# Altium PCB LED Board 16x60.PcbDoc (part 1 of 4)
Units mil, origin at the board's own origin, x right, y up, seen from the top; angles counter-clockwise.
Board outline 17002.17 x 16958.87 mil, 2 copper layers (Top Layer, Bottom Layer); 984 components, 0 nets, 1968 pads, 0 vias.

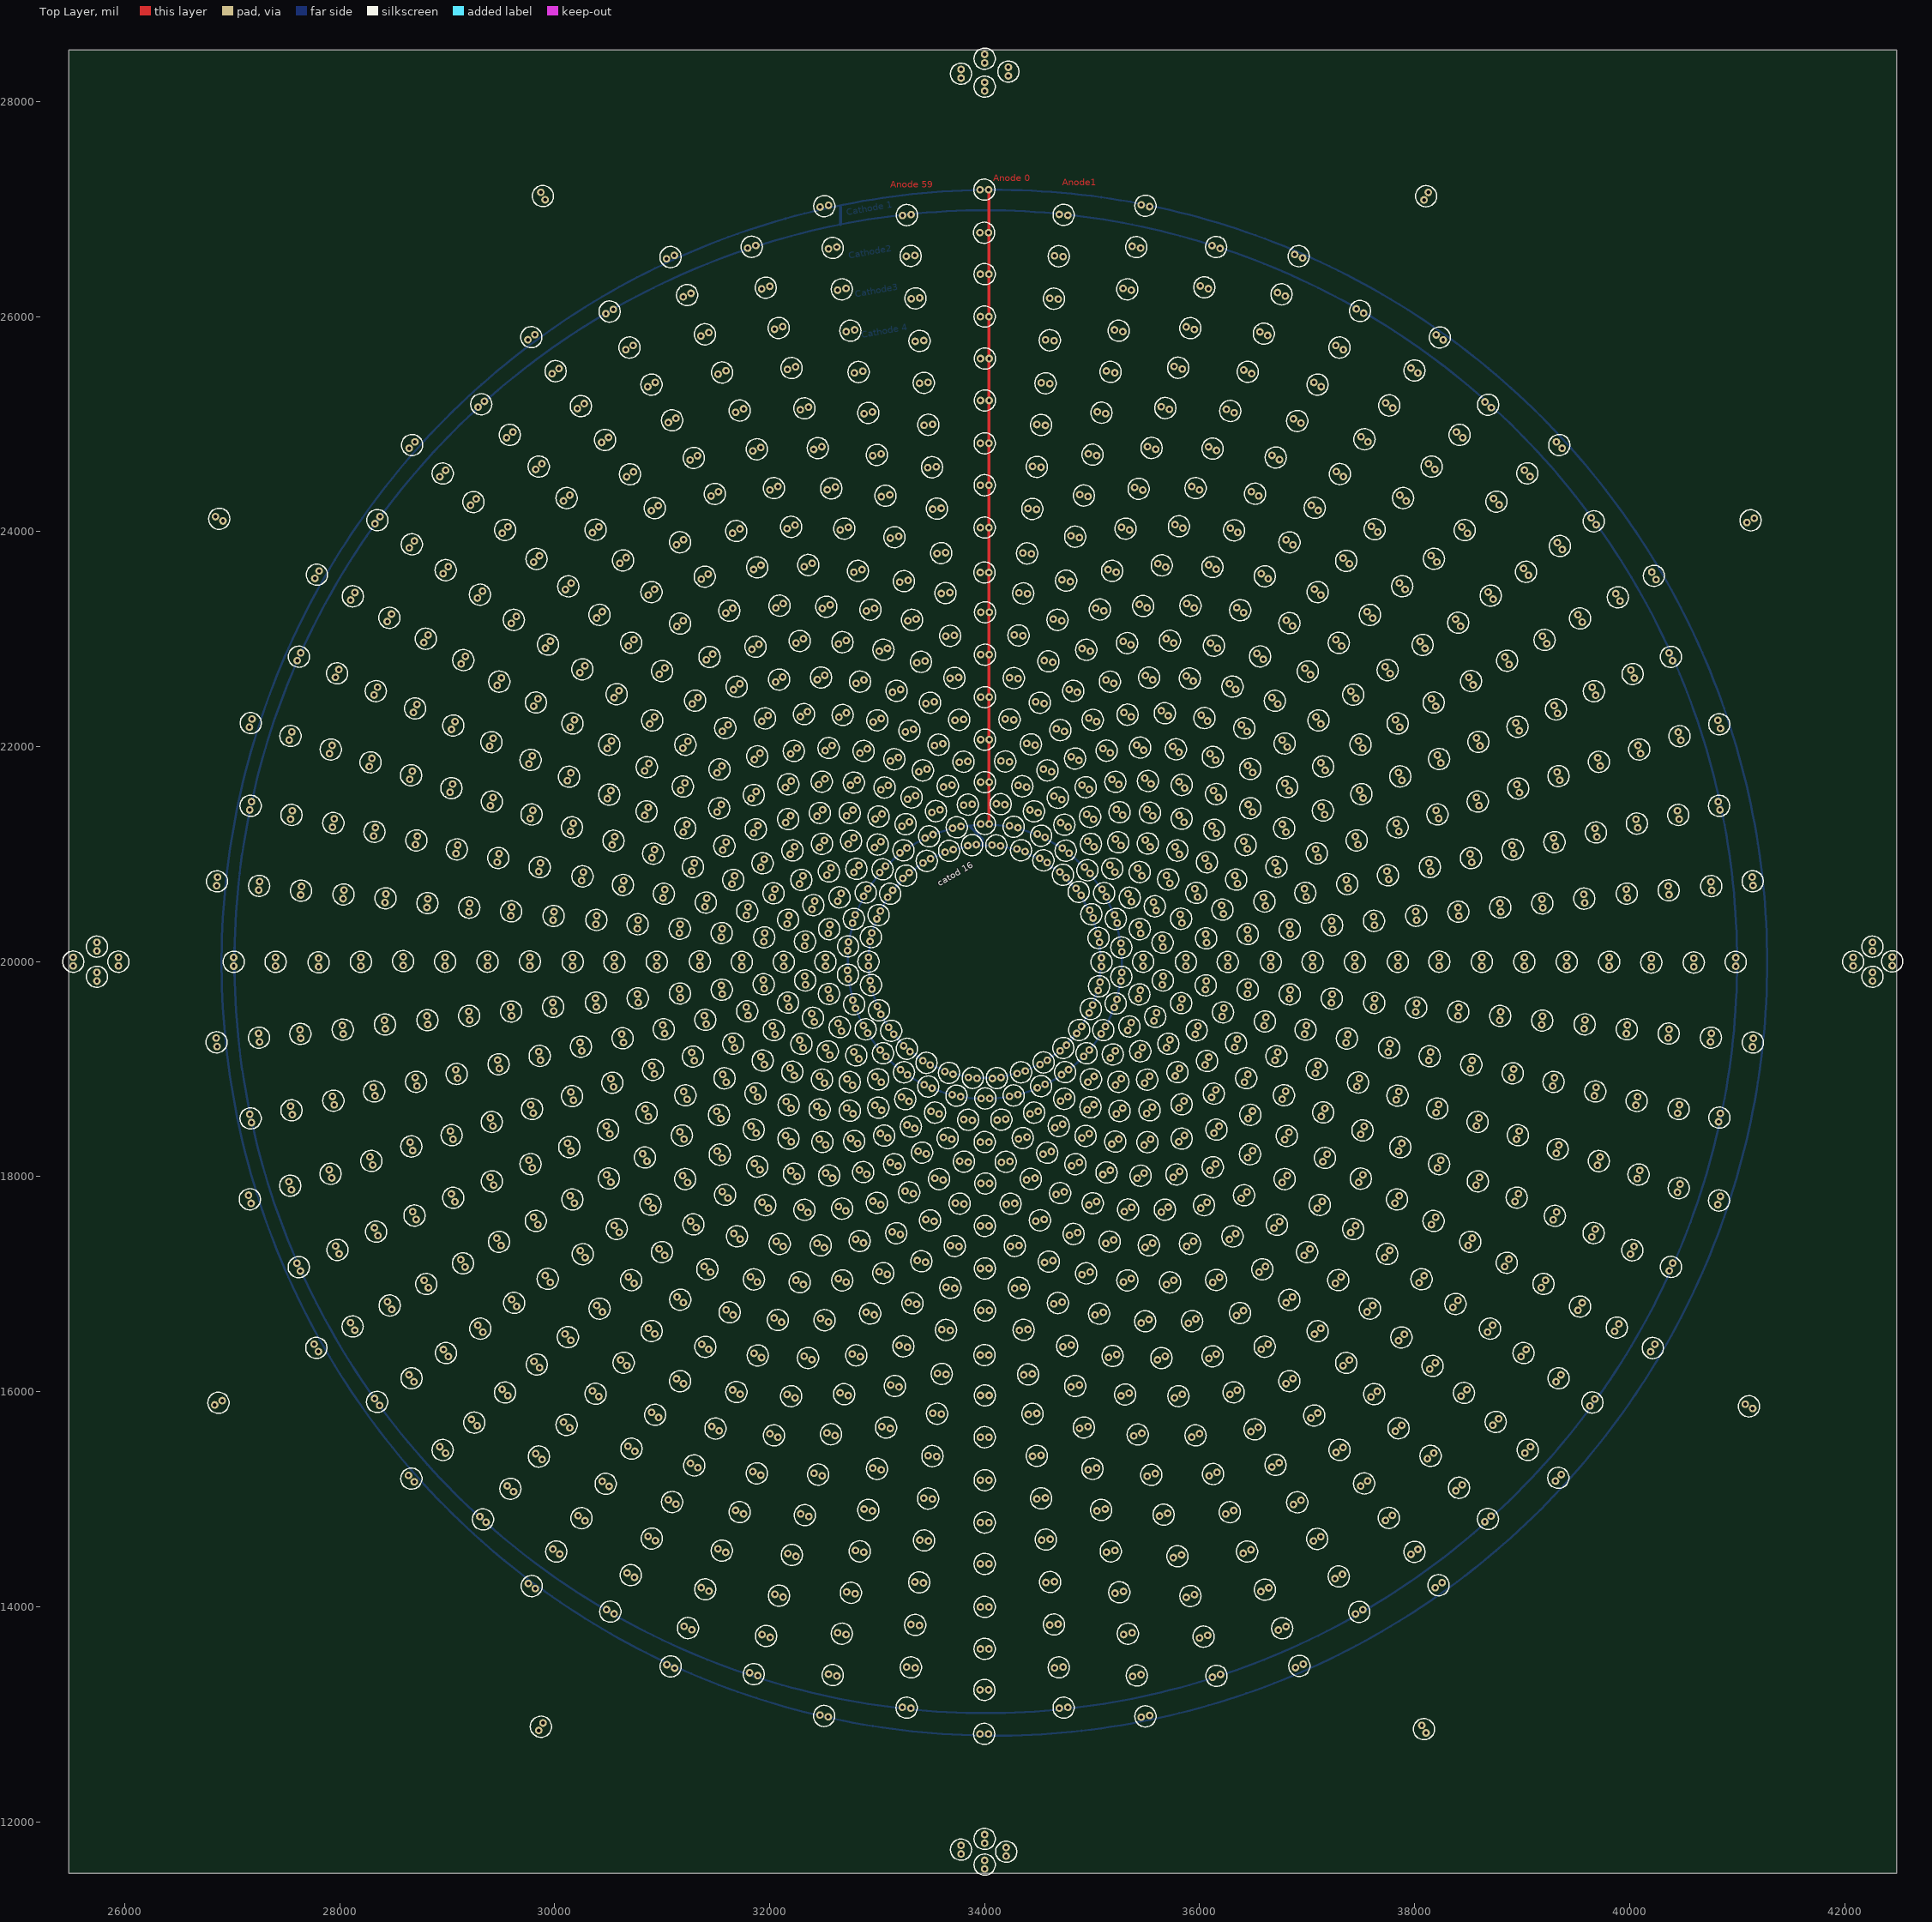
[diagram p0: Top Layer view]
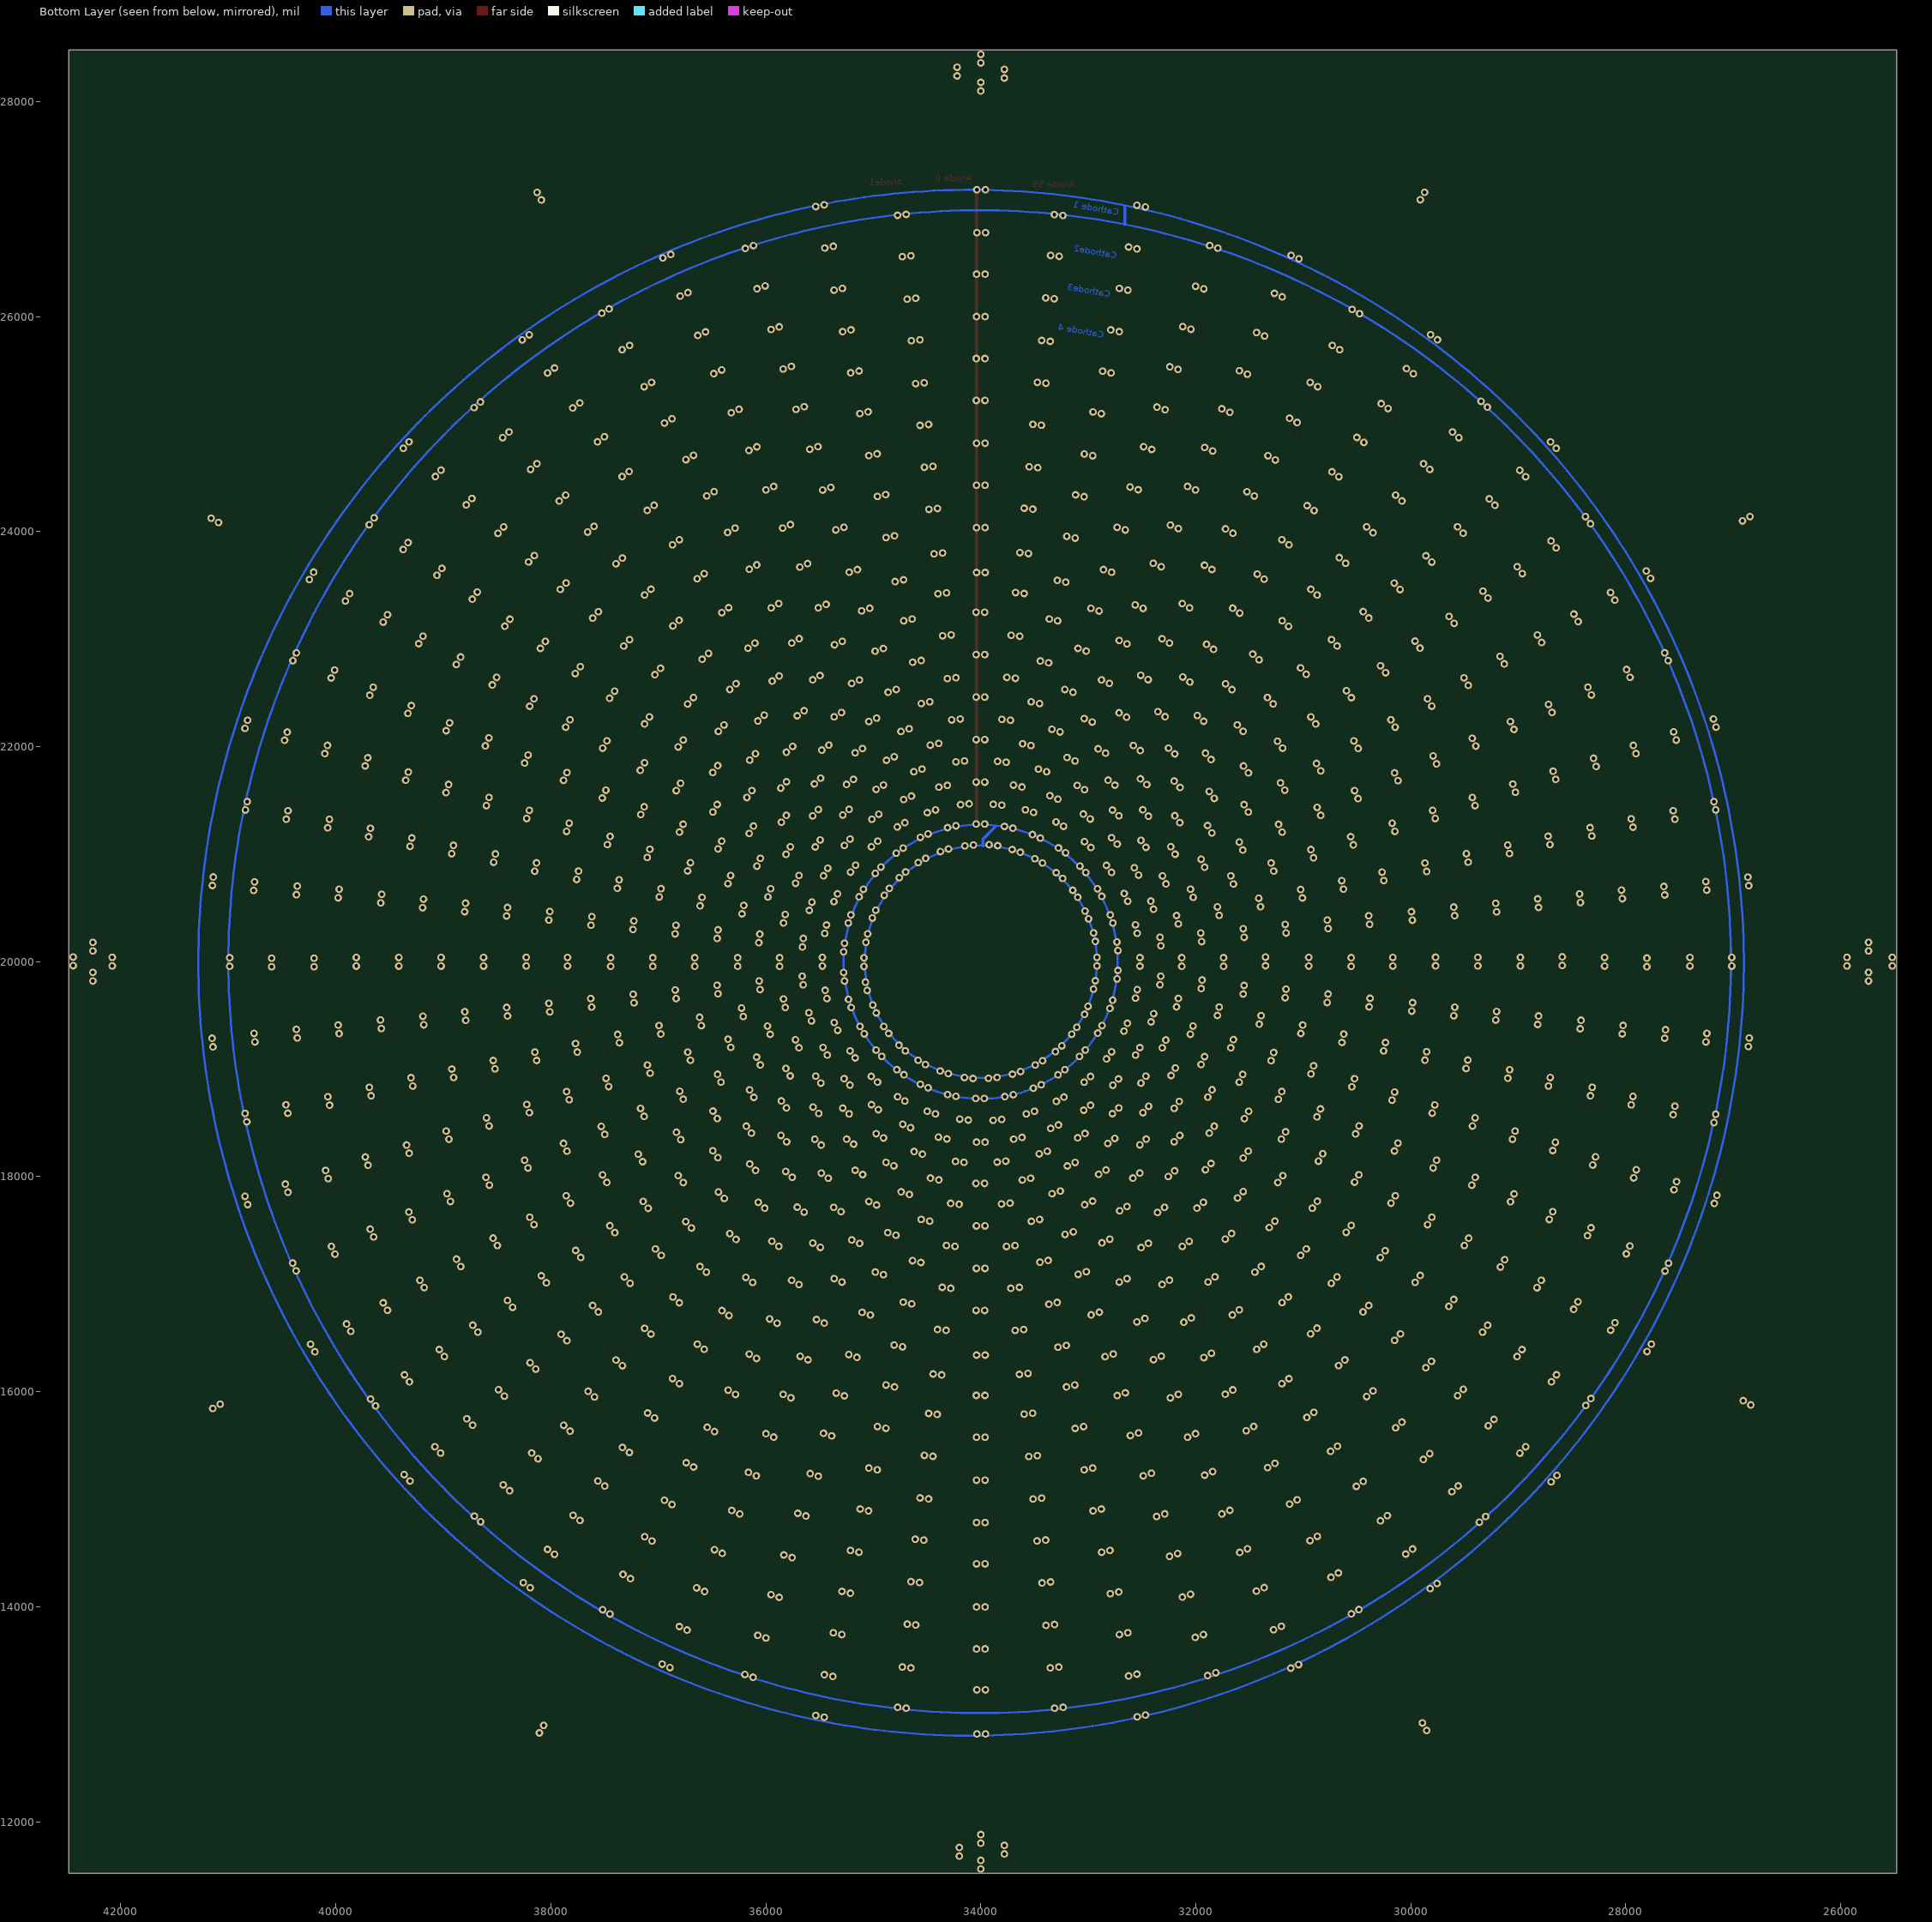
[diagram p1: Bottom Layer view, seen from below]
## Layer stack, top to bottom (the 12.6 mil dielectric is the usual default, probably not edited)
Top Layer: signal copper 1.4
Dielectric: dielectric 12.6, FR-4, Dk 4.8
Bottom Layer: signal copper 1.4

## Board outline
25480.57,11520.57 42482.74,11520.57 42482.74,28479.43 25480.57,28479.43

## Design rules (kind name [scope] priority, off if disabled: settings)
Clearance [All] p1: gap=10
PolygonConnect [All] p1: connectstyle=Relief reliefconductorwidth=10 reliefentries=4 polygonreliefangle="90 Angle"
RoutingVias [All] p1: holewidth=28 width=50 viastyle="Through Hole" minholewidth=28 minwidth=50 maxholewidth=28 maxwidth=50
SilkscreenOverComponentPads [All] p1: minsilkscreentomaskgap=10
SolderMaskExpansion [All] p1: expansion=4
Width [All] p1: maxlimit=10 minlimit=10 preferedwidth=10
27 further rules are at their usual default settings.

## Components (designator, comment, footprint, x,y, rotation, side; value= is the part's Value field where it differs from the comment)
? "" "LED 5MM"#1 33273.72,13060.04 r354 top
? "" "LED 5MM"#2 32585.57,13363.9 r348 top
? "" "LED 5MM"#3 31850.9,13372.36 r342 top
? "" "LED 5MM"#4 31239.7,13801.26 r336 top
? "" "LED 5MM"#5 30517.32,13953.56 r330 top
? "" "LED 5MM"#6 30013.82,14512.85 r324 top
? "" "LED 5MM"#7 29332.22,14811.71 r318 top
? "" "LED 5MM"#8 28956.81,15457.17 r312 top
? "" "LED 5MM"#9 28347.15,15904.51 r306 top
? "" "LED 5MM"#10 28119.06,16606.48 r300 top
? "" "LED 5MM"#11 27617.85,17158.44 r294 top
? "" "LED 5MM"#12 27538.23,17916.2 r288 top
? "" "LED 5MM"#13 27170.12,18542.03 r282 top
? "" "LED 5MM"#14 27248.21,19292.85 r276 top
? "" "LED 5MM"#15 27012.42,19998.68 r270 top
? "" "LED 5MM"#16 27249.37,20705.29 r264 top
? "" "LED 5MM"#17 27170.12,21449.96 r78 top
? "" "LED 5MM"#18 27541.32,22099.25 r72 top
? "" "LED 5MM"#19 27619.78,22837.01 r66 top
? "" "LED 5MM"#20 28120.98,23398.98 r60 top
? "" "LED 5MM"#21 28350.22,24107.11 r54 top
? "" "LED 5MM"#22 28957.58,24540.98 r48 top
? "" "LED 5MM"#23 29316.08,25185.67 r42 top
? "" "LED 5MM"#24 30007.68,25493.38 r36 top
? "" "LED 5MM"#25 30510.02,26048.03 r30 top
? "" "LED 5MM"#26 31231.61,26201.12 r24 top
? "" "LED 5MM"#27 31832.81,26650.02 r18 top
? "" "LED 5MM"#28 32585.89,26639.68 r12 top
? "" "LED 5MM"#29 33275.63,26945.43 r6 top
? "" "LED 5MM"#30 33994.92,26781.18 r0 top
? "" "LED 5MM"#31 34734.21,26947.34 r354 top
? "" "LED 5MM"#32 35410.79,26646.93 r348 top
? "" "LED 5MM"#33 36153.19,26648.09 r342 top
? "" "LED 5MM"#34 36761.1,26207.97 r336 top
? "" "LED 5MM"#35 37491.75,26053.03 r330 top
? "" "LED 5MM"#36 37998.33,25499.53 r324 top
? "" "LED 5MM"#37 38683.78,25180.67 r318 top
? "" "LED 5MM"#38 39047.85,24543.01 r312 top
? "" "LED 5MM"#39 39666.16,24096.73 r306 top
? "" "LED 5MM"#40 39891.38,23389.45 r300 top
? "" "LED 5MM"#41 40384.06,22835.83 r294 top
? "" "LED 5MM"#42 40464.37,22098.11 r288 top
? "" "LED 5MM"#43 40832.79,21449.96 r282 top
? "" "LED 5MM"#44 40760.18,20702.99 r276 top
? "" "LED 5MM"#45 40987.44,19997.54 r270 top
? "" "LED 5MM"#46 40756.71,19292.85 r264 top
? "" "LED 5MM"#47 40835.89,18549.33 r258 top
? "" "LED 5MM"#48 40457.83,17893.48 r252 top
? "" "LED 5MM"#49 40385.08,17160.37 r246 top
? "" "LED 5MM"#50 39880.87,16596.06 r240 top
? "" "LED 5MM"#51 39653.86,15899.51 r234 top
? "" "LED 5MM"#52 39052.32,15458.27 r228 top
? "" "LED 5MM"#53 38682.62,14815.94 r222 top
? "" "LED 5MM"#54 37998.39,14509.72 r216 top
? "" "LED 5MM"#55 37484.06,13951.26 r210 top
? "" "LED 5MM"#56 36767.87,13798.88 r204 top
? "" "LED 5MM"#57 36157.03,13356.22 r198 top
? "" "LED 5MM"#58 35415.45,13359.61 r192 top
? "" "LED 5MM"#59 34734.21,13060.04 r186 top
? "" "LED 5MM"#60 33996.85,13225.79 r0 top
? "" "LED 5MM"#61 33353.72,13830.04 r354 top
? "" "LED 5MM"#62 32755.57,14128.9 r348 top
? "" "LED 5MM"#63 32085.9,14102.36 r342 top
? "" "LED 5MM"#64 31554.7,14521.26 r336 top
? "" "LED 5MM"#65 30902.32,14633.56 r330 top
? "" "LED 5MM"#66 30473.82,15142.85 r324 top
? "" "LED 5MM"#67 29852.22,15396.71 r318 top
? "" "LED 5MM"#68 29536.81,15992.17 r312 top
? "" "LED 5MM"#69 28987.15,16359.51 r306 top
? "" "LED 5MM"#70 28804.06,17001.48 r300 top
? "" "LED 5MM"#71 28337.85,17488.44 r294 top
? "" "LED 5MM"#72 28293.23,18146.2 r288 top
? "" "LED 5MM"#73 27940.12,18707.03 r282 top
? "" "LED 5MM"#74 28028.21,19367.85 r276 top
? "" "LED 5MM"#75 27802.42,19993.68 r270 top
? "" "LED 5MM"#76 28034.37,20625.29 r264 top
? "" "LED 5MM"#77 27940.12,21289.96 r78 top
? "" "LED 5MM"#78 28286.32,21854.25 r72 top
? "" "LED 5MM"#79 28334.78,22517.01 r66 top
? "" "LED 5MM"#80 28800.98,23003.98 r60 top
? "" "LED 5MM"#81 28985.22,23642.11 r54 top
? "" "LED 5MM"#82 29537.58,24015.98 r48 top
? "" "LED 5MM"#83 29851.08,24605.67 r42 top
? "" "LED 5MM"#84 30467.68,24853.38 r36 top
? "" "LED 5MM"#85 30900.02,25368.03 r30 top
? "" "LED 5MM"#86 31556.61,25481.12 r24 top
? "" "LED 5MM"#87 32082.81,25895.02 r18 top
? "" "LED 5MM"#88 32750.57,25869.63 r12 top
? "" "LED 5MM"#89 33355.63,26170.43 r6 top
? "" "LED 5MM"#90 33999.92,26001.18 r0 top
? "" "LED 5MM"#91 34644.21,26167.34 r354 top
? "" "LED 5MM"#92 35246.2,25869.63 r348 top
? "" "LED 5MM"#93 35913.19,25893.09 r342 top
? "" "LED 5MM"#94 36447.09,25487.28 r336 top
? "" "LED 5MM"#95 37096.75,25368.03 r330 top
? "" "LED 5MM"#96 37533.33,24859.53 r324 top
? "" "LED 5MM"#97 38158.78,24605.67 r318 top
? "" "LED 5MM"#98 38465.35,24014.07 r312 top
? "" "LED 5MM"#99 39036.16,23626.73 r306 top
? "" "LED 5MM"#100 39208.88,22992.81 r300 top
? "" "LED 5MM"#101 39668.15,22515.85 r294 top
? "" "LED 5MM"#102 39714.7,21859.25 r288 top
? "" "LED 5MM"#103 40067.79,21284.96 r282 top
? "" "LED 5MM"#104 39973.56,20633.37 r276 top
? "" "LED 5MM"#105 40202.44,19992.54 r270 top
? "" "LED 5MM"#106 39973.56,19370.94 r264 top
? "" "LED 5MM"#107 40065.89,18704.33 r258 top
? "" "LED 5MM"#108 39713.54,18145.06 r252 top
? "" "LED 5MM"#109 39665.08,17475.37 r246 top
? "" "LED 5MM"#110 39198.88,17002.24 r240 top
? "" "LED 5MM"#111 39013.86,16359.51 r234 top
? "" "LED 5MM"#112 38459.19,15988.31 r228 top
? "" "LED 5MM"#113 38148.29,15402.52 r222 top
? "" "LED 5MM"#114 37530.25,15145.92 r216 top
? "" "LED 5MM"#115 37092.82,14630.53 r210 top
? "" "LED 5MM"#116 36441.32,14513.17 r204 top
? "" "LED 5MM"#117 35913.88,14098.96 r198 top
? "" "LED 5MM"#118 35252.34,14133.9 r192 top
? "" "LED 5MM"#119 34644.15,13833.94 r186 top
? "" "LED 5MM"#120 33999.88,13997.82 r0 top
? "" "LED 5MM"#121 35189.83,16332.24 r198 top
? "" "LED 5MM"#122 34403.84,16160.39 r186 top
? "" "LED 5MM"#123 33600.44,16165.06 r354 top
? "" "LED 5MM"#124 32805.82,16338.11 r342 top
? "" "LED 5MM"#125 32076.09,16666.48 r330 top
? "" "LED 5MM"#126 31419.34,17138.56 r318 top
? "" "LED 5MM"#127 30891.41,17739.66 r306 top
? "" "LED 5MM"#128 30495.84,18434.67 r294 top
? "" "LED 5MM"#129 30243.28,19208.98 r282 top
? "" "LED 5MM"#130 30166.78,19998.97 r270 top
? "" "LED 5MM"#131 30258.28,20793.86 r78 top
? "" "LED 5MM"#132 30506.35,21553.78 r66 top
? "" "LED 5MM"#133 30906.15,22244.15 r54 top
? "" "LED 5MM"#134 31439.46,22834.9 r42 top
? "" "LED 5MM"#135 32091.35,23311.85 r30 top
? "" "LED 5MM"#136 32820.44,23635.08 r18 top
? "" "LED 5MM"#137 33595.55,23800.61 r6 top
? "" "LED 5MM"#138 34395.07,23798.03 r354 top
? "" "LED 5MM"#139 35185.19,23635.45 r342 top
? "" "LED 5MM"#140 35914.68,23311.61 r330 top
? "" "LED 5MM"#141 36561.92,22840.14 r318 top
? "" "LED 5MM"#142 37104.97,22244.38 r306 top
? "" "LED 5MM"#143 37504.18,21558.52 r294 top
? "" "LED 5MM"#144 37751.25,20803.6 r282 top
? "" "LED 5MM"#145 36122.57,21904.92 r312 top
? "" "LED 5MM"#146 36471.56,21427.52 r300 top
? "" "LED 5MM"#147 36714.3,20882.12 r288 top
? "" "LED 5MM"#148 36838.95,20298.25 r276 top
? "" "LED 5MM"#149 36838.22,19696.32 r264 top
? "" "LED 5MM"#150 36713.95,19120.71 r252 top
? "" "LED 5MM"#151 36471.07,18575.55 r240 top
? "" "LED 5MM"#152 36122.22,18088.52 r228 top
? "" "LED 5MM"#153 35675.88,17692.95 r216 top
? "" "LED 5MM"#154 35163.08,17395.61 r204 top
? "" "LED 5MM"#155 34595.87,17210.01 r192 top
? "" "LED 5MM"#156 34269.72,18755.55 r192 top
? "" "LED 5MM"#157 34006.71,18727.78 r180 top
? "" "LED 5MM"#158 33737.22,18753.7 r348 top
? "" "LED 5MM"#159 33474.19,18838.9 r336 top
? "" "LED 5MM"#160 33249.15,18971.34 r324 top
? "" "LED 5MM"#161 33054.67,19148.23 r312 top
? "" "LED 5MM"#162 32891.67,19370.49 r300 top
? "" "LED 5MM"#163 32785.18,19603.88 r288 top
? "" "LED 5MM"#164 32727.76,19878.92 r276 top
? "" "LED 5MM"#165 32728.68,20142.87 r264 top
? "" "LED 5MM"#166 32783.33,20397.54 r72 top
? "" "LED 5MM"#167 32893.52,20642.97 r60 top
? "" "LED 5MM"#168 33050.04,20858.74 r48 top
? "" "LED 5MM"#169 33243.6,21035.63 r36 top
? "" "LED 5MM"#170 33482.54,21166.22 r24 top
? "" "LED 5MM"#171 33740.37,21250.35 r12 top
? "" "LED 5MM"#172 34002.09,21281.04 r0 top
? "" "LED 5MM"#173 34269.72,21255.12 r348 top
? "" "LED 5MM"#174 34525.33,21171.77 r336 top
? "" "LED 5MM"#175 34754.07,21032.85 r324 top
? "" "LED 5MM"#176 34955.04,20850.41 r312 top
? "" "LED 5MM"#177 35111.56,20638.33 r300 top
? "" "LED 5MM"#178 35219.92,20397.54 r288 top
? "" "LED 5MM"#179 35271.77,20131.75 r276 top
? "" "LED 5MM"#180 35271.77,19859.47 r264 top
? "" "LED 5MM"#181 35218.07,19611.28 r252 top
? "" "LED 5MM"#182 35103.23,19363.09 r240 top
? "" "LED 5MM"#183 34947.64,19148.23 r228 top
? "" "LED 5MM"#184 34747.6,18972.26 r216 top
? "" "LED 5MM"#185 34525.33,18842.62 r204 top
? "" "LED 5MM"#186 34987.85,19560.04 r246 top
? "" "LED 5MM"#187 34879.22,19364.69 r234 top
? "" "LED 5MM"#188 34731.21,19197.36 r222 top
? "" "LED 5MM"#189 34548.51,19062.66 r210 top
? "" "LED 5MM"#190 34339.07,18971.06 r198 top
? "" "LED 5MM"#191 34112.45,18917.36 r186 top
? "" "LED 5MM"#192 33888.91,18919.03 r354 top
? "" "LED 5MM"#193 33667.87,18965.35 r342 top
? "" "LED 5MM"#194 33458.48,19059.03 r330 top
? "" "LED 5MM"#195 33275.43,19190 r318 top
? "" "LED 5MM"#196 33130.05,19356.94 r306 top
? "" "LED 5MM"#197 33017.41,19547.32 r294 top
? "" "LED 5MM"#198 32942.43,19783.54 r282 top
? "" "LED 5MM"#199 32918.91,20000.63 r270 top
? "" "LED 5MM"#200 32941.25,20228.25 r78 top
? "" "LED 5MM"#201 33012.74,20434.01 r66 top
? "" "LED 5MM"#202 33120.22,20631.89 r54 top
? "" "LED 5MM"#203 33268.59,20801.26 r42 top
? "" "LED 5MM"#204 33461.33,20937.4 r30 top
? "" "LED 5MM"#205 33669.13,21030.96 r18 top
? "" "LED 5MM"#206 33881.82,21083.76 r6 top
? "" "LED 5MM"#207 34107.9,21081.24 r354 top
? "" "LED 5MM"#208 34458.66,21398.66 r342 top
? "" "LED 5MM"#209 34546.63,20942.37 r330 top
? "" "LED 5MM"#210 34728.65,20808.11 r318 top
? "" "LED 5MM"#211 34874.14,20649.42 r306 top
? "" "LED 5MM"#212 34992.59,20442 r294 top
? "" "LED 5MM"#213 35060,20220 r282 top
? "" "LED 5MM"#214 35086.84,19995.51 r270 top
? "" "LED 5MM"#215 35064.6,19771.24 r258 top
? "" "LED 5MM"#216 32328.6,20187.32 r264 top
? "" "LED 5MM"#217 26857.85,20747.01 r264 top
? "" "LED 5MM"#218 27639.37,20660.29 r264 top
? "" "LED 5MM"#219 28814.8,20544.86 r264 top
? "" "LED 5MM"#220 30771.46,20347.78 r264 top
? "" "LED 5MM"#221 29988.82,20425.29 r264 top
? "" "LED 5MM"#222 29204.34,20503.13 r264 top
? "" "LED 5MM"#223 31553.44,20266.04 r264 top
? "" "LED 5MM"#224 41146.71,19247.85 r264 top
? "" "LED 5MM"#225 35657.05,19825.22 r264 top
? "" "LED 5MM"#226 36447.93,19740.92 r264 top
? "" "LED 5MM"#227 37229.49,19656.53 r264 top
? "" "LED 5MM"#228 39186.48,19452.46 r264 top
? "" "LED 5MM"#229 38796.17,19494.94 r264 top
? "" "LED 5MM"#230 38014.39,19572.79 r264 top
? "" "LED 5MM"#231 40363.56,19330.94 r264 top
? "" "LED 5MM"#232 36927.87,13448.88 r204 top
? "" "LED 5MM"#233 36606.32,14158.17 r204 top
? "" "LED 5MM"#234 36124.68,15233.62 r204 top
? "" "LED 5MM"#235 35962.06,15593.58 r204 top
? "" "LED 5MM"#236 35644.07,16312.56 r204 top
? "" "LED 5MM"#237 35327.56,17035.02 r204 top
? "" "LED 5MM"#238 35005.06,17752.58 r204 top
? "" "LED 5MM"#239 36037.03,13721.22 r198 top
? "" "LED 5MM"#240 35793.88,14468.96 r198 top
? "" "LED 5MM"#241 35549.25,15225.94 r198 top
? "" "LED 5MM"#242 35306.91,15973.7 r198 top
? "" "LED 5MM"#243 35064.98,16725.59 r198 top
? "" "LED 5MM"#244 34943.09,17100.63 r198 top
? "" "LED 5MM"#245 34581.83,18222.11 r198 top
? "" "LED 5MM"#246 34195.63,18137.83 r186 top
? "" "LED 5MM"#247 34318.9,16966.36 r186 top
? "" "LED 5MM"#248 34362.4,16575.14 r186 top
? "" "LED 5MM"#249 34444.53,15793.68 r186 top
? "" "LED 5MM"#250 34524.55,15007.46 r186 top
? "" "LED 5MM"#251 34609.15,14228.94 r186 top
? "" "LED 5MM"#252 34689.21,13435.04 r186 top
? "" "LED 5MM"#253 34514.21,17594.21 r192 top
? "" "LED 5MM"#254 34681.75,16824.94 r192 top
? "" "LED 5MM"#255 34841.87,16053.05 r192 top
? "" "LED 5MM"#256 35002.07,15281.71 r192 top
? "" "LED 5MM"#257 35083.05,14899.76 r192 top
? "" "LED 5MM"#258 35332.34,13748.9 r192 top
? "" "LED 5MM"#259 35495.45,12979.61 r192 top
? "" "LED 5MM"#260 34938.39,18379.55 r210 top
? "" "LED 5MM"#261 35527.46,17361.81 r210 top
? "" "LED 5MM"#262 35724.98,17016.56 r210 top
? "" "LED 5MM"#263 36120.06,16329.11 r210 top
? "" "LED 5MM"#264 36510.87,15649.06 r210 top
? "" "LED 5MM"#265 36907.82,14970.53 r210 top
? "" "LED 5MM"#266 37294.06,14281.26 r210 top
? "" "LED 5MM"#267 35450.51,18009.11 r216 top
? "" "LED 5MM"#268 35910.9,17375.65 r216 top
? "" "LED 5MM"#269 36375.04,16731.28 r216 top
? "" "LED 5MM"#270 36835.13,16097.79 r216 top
? "" "LED 5MM"#271 37066.3,15778.29 r216 top
? "" "LED 5MM"#272 37760.26,14825.92 r216 top
? "" "LED 5MM"#273 38223.39,14199.72 r216 top
? "" "LED 5MM"#274 35254.17,18611.08 r222 top
? "" "LED 5MM"#275 36039.61,17735.02 r222 top
? "" "LED 5MM"#276 36305.49,17443.78 r222 top
? "" "LED 5MM"#277 36833.98,16853.78 r222 top
? "" "LED 5MM"#278 37363.25,16267.56 r222 top
? "" "LED 5MM"#279 37850,15660 r222 top
? "" "LED 5MM"#280 38412.62,15105.94 r222 top
? "" "LED 5MM"#281 35832.07,18353.62 r228 top
? "" "LED 5MM"#282 36413.37,17827.01 r228 top
? "" "LED 5MM"#283 36999.55,17297.6 r228 top
? "" "LED 5MM"#284 37584.54,16772.36 r228 top
? "" "LED 5MM"#285 37877.14,16504.51 r228 top
? "" "LED 5MM"#286 38754.19,15718.31 r228 top
? "" "LED 5MM"#287 39337.32,15198.27 r228 top
? "" "LED 5MM"#288 39338.86,16124.51 r234 top
? "" "LED 5MM"#289 38701.83,16586.06 r234 top
? "" "LED 5MM"#290 38064.84,17046.1 r234 top
? "" "LED 5MM"#291 37427.87,17512.28 r234 top
? "" "LED 5MM"#292 36790.9,17977.46 r234 top
? "" "LED 5MM"#293 36469.33,18209.19 r234 top
? "" "LED 5MM"#294 35511.63,18902.81 r234 top
? "" "LED 5MM"#295 40215.87,16406.06 r240 top
? "" "LED 5MM"#296 39538.88,16792.24 r240 top
? "" "LED 5MM"#297 38517.18,17393.82 r240 top
? "" "LED 5MM"#298 38176.33,17587.99 r240 top
? "" "LED 5MM"#299 37499.17,17981.71 r240 top
? "" "LED 5MM"#300 36810.79,18379.13 r240 top
? "" "LED 5MM"#301 36131.2,18772.22 r240 top
? "" "LED 5MM"#302 40025.08,17315.37 r246 top
? "" "LED 5MM"#303 39304.96,17635.37 r246 top
? "" "LED 5MM"#304 38587.97,17956.95 r246 top
? "" "LED 5MM"#305 37866.36,18273.9 r246 top
? "" "LED 5MM"#306 37148.58,18597.72 r246 top
? "" "LED 5MM"#307 36784.19,18757.46 r246 top
? "" "LED 5MM"#308 35707.97,19236.2 r246 top
? "" "LED 5MM"#309 40832.83,17778.48 r252 top
? "" "LED 5MM"#310 40083.54,18020.06 r252 top
? "" "LED 5MM"#311 38960.32,18386.22 r252 top
? "" "LED 5MM"#312 38585.93,18508.97 r252 top
? "" "LED 5MM"#313 37841.22,18753.84 r252 top
? "" "LED 5MM"#314 37088.98,19000.81 r252 top
? "" "LED 5MM"#315 36338.66,19240.83 r252 top
? "" "LED 5MM"#316 35827.44,19614.06 r258 top
? "" "LED 5MM"#317 36985.16,19366.83 r258 top
? "" "LED 5MM"#318 37370,19284.69 r258 top
? "" "LED 5MM"#319 38140.24,19120.12 r258 top
? "" "LED 5MM"#320 38912.62,18961.65 r258 top
? "" "LED 5MM"#321 39680.37,18792.4 r258 top
? "" "LED 5MM"#322 40455.89,18629.33 r258 top
? "" "LED 5MM"#323 38086.44,12860.67 r300 top
? "" "LED 5MM"#324 41111.16,15863.9 r330 top
? "" "LED 5MM"#325 34155.81,18530.51 r186 top
? "" "LED 5MM"#326 34354,18359.17 r192 top
? "" "LED 5MM"#327 34459.59,18596.26 r198 top
? "" "LED 5MM"#328 34689.25,18471.24 r204 top
? "" "LED 5MM"#329 34740.2,18724.07 r210 top
? "" "LED 5MM"#330 34984.68,18646.28 r216 top
? "" "LED 5MM"#331 34989.31,18906.51 r222 top
? "" "LED 5MM"#332 35244,18882.44 r228 top
? "" "LED 5MM"#333 35192.13,19137.11 r234 top
? "" "LED 5MM"#334 35447.74,19166.75 r240 top
? "" "LED 5MM"#335 35346.79,19397.34 r246 top
? "" "LED 5MM"#336 35586.65,19487.19 r252 top
? "" "LED 5MM"#337 35439.41,19695.55 r258 top
? "" "LED 5MM"#338 31076.48,26554.76 r24 top
? "" "LED 5MM"#339 31396.61,25836.12 r24 top
? "" "LED 5MM"#340 31879.69,24766.77 r24 top
? "" "LED 5MM"#341 32038.71,24405 r24 top
? "" "LED 5MM"#342 32358.15,23689.96 r24 top
? "" "LED 5MM"#343 32676.22,22972.15 r24 top
? "" "LED 5MM"#344 33000.04,22245.14 r24 top
? "" "LED 5MM"#345 31962.81,26270.02 r18 top
? "" "LED 5MM"#346 32202.79,25522.22 r18 top
? "" "LED 5MM"#347 32447.44,24777.54 r18 top
? "" "LED 5MM"#348 32693.6,24028.25 r18 top
? "" "LED 5MM"#349 32937.38,23274.47 r18 top
? "" "LED 5MM"#350 33057.54,22901.79 r18 top
? "" "LED 5MM"#351 33425.12,21779.29 r18 top
? "" "LED 5MM"#352 33802.97,21859.86 r6 top
? "" "LED 5MM"#353 33678.03,23031.46 r6 top
? "" "LED 5MM"#354 33635.71,23429.17 r6 top
? "" "LED 5MM"#355 33555.22,24214.41 r6 top
? "" "LED 5MM"#356 33475.22,24994.49 r6 top
? "" "LED 5MM"#357 33393.68,25774.55 r6 top
? "" "LED 5MM"#358 33310.63,26565.43 r6 top
? "" "LED 5MM"#359 33491.79,22409.06 r12 top
? "" "LED 5MM"#360 33323.44,23179.37 r12 top
? "" "LED 5MM"#361 33160.63,23948.6 r12 top
? "" "LED 5MM"#362 32997.32,24714.29 r12 top
? "" "LED 5MM"#363 32916.71,25105.26 r12 top
? "" "LED 5MM"#364 32670.57,26254.63 r12 top
? "" "LED 5MM"#365 32507.93,27027.83 r12 top
? "" "LED 5MM"#366 33068.56,21620 r30 top
? "" "LED 5MM"#367 32476.85,22643.4 r30 top
? "" "LED 5MM"#368 32278.8,22983.5 r30 top
? "" "LED 5MM"#369 31884.31,23668.21 r30 top
? "" "LED 5MM"#370 31488.9,24351.34 r30 top
? "" "LED 5MM"#371 31091.93,25036.02 r30 top
? "" "LED 5MM"#372 30695.02,25713.03 r30 top
? "" "LED 5MM"#373 32548.09,21987.68 r36 top
? "" "LED 5MM"#374 32087.19,22624.41 r36 top
? "" "LED 5MM"#375 31623.64,23265.49 r36 top
? "" "LED 5MM"#376 31165.27,23901.51 r36 top
? "" "LED 5MM"#377 30930.37,24219.03 r36 top
? "" "LED 5MM"#378 30242.68,25168.38 r36 top
? "" "LED 5MM"#379 29782.22,25809.35 r36 top
? "" "LED 5MM"#380 32744.43,21383.86 r42 top
? "" "LED 5MM"#381 31955.45,22262.77 r42 top
? "" "LED 5MM"#382 31692.62,22557.7 r42 top
? "" "LED 5MM"#383 31165.79,23145.08 r42 top
? "" "LED 5MM"#384 30634.96,23732.83 r42 top
? "" "LED 5MM"#385 30110.31,24312.87 r42 top
? "" "LED 5MM"#386 29581.08,24900.67 r42 top
? "" "LED 5MM"#387 32173.01,21650.57 r48 top
? "" "LED 5MM"#388 31586.16,22173.05 r48 top
? "" "LED 5MM"#389 30998.56,22703.42 r48 top
? "" "LED 5MM"#390 30415.86,23226.95 r48 top
? "" "LED 5MM"#391 30125.69,23491.28 r48 top
? "" "LED 5MM"#392 29242.58,24275.98 r48 top
? "" "LED 5MM"#393 28672.26,24805.88 r48 top
? "" "LED 5MM"#394 28670.22,23882.11 r54 top
? "" "LED 5MM"#395 29304.09,23414.35 r54 top
? "" "LED 5MM"#396 29936.46,22949.69 r54 top
? "" "LED 5MM"#397 30574.96,22488.11 r54 top
? "" "LED 5MM"#398 31215.71,22018.35 r54 top
? "" "LED 5MM"#399 31532.22,21788.62 r54 top
? "" "LED 5MM"#400 32486.04,21095.83 r54 top
? "" "LED 5MM"#401 27787.6,23599.69 r60 top
? "" "LED 5MM"#402 28460.98,23198.98 r60 top
? "" "LED 5MM"#403 29484.09,22605.04 r60 top
? "" "LED 5MM"#404 29824.06,22410.77 r60 top
? "" "LED 5MM"#405 30507.78,22018.66 r60 top
? "" "LED 5MM"#406 31191.57,21629.43 r60 top
? "" "LED 5MM"#407 31870.18,21231.97 r60 top
? "" "LED 5MM"#408 27974.78,22682.01 r66 top
? "" "LED 5MM"#409 28700.96,22355.79 r66 top
? "" "LED 5MM"#410 29410.26,22041.91 r66 top
? "" "LED 5MM"#411 30133.38,21720.35 r66 top
? "" "LED 5MM"#412 30853.78,21398.09 r66 top
? "" "LED 5MM"#413 31212.72,21241.28 r66 top
? "" "LED 5MM"#414 32293.4,20760.57 r66 top
? "" "LED 5MM"#415 27171.18,22219.43 r72 top
? "" "LED 5MM"#416 27916.32,21974.25 r72 top
? "" "LED 5MM"#417 29037.91,21614.19 r72 top
? "" "LED 5MM"#418 29413.83,21489.09 r72 top
? "" "LED 5MM"#419 30159.59,21249.33 r72 top
? "" "LED 5MM"#420 30916.22,21004.92 r72 top
? "" "LED 5MM"#421 31660.88,20760.57 r72 top
? "" "LED 5MM"#422 32170.24,20390.14 r78 top
? "" "LED 5MM"#423 31015.45,20631.91 r78 top
? "" "LED 5MM"#424 30633.78,20713.96 r78 top
? "" "LED 5MM"#425 29859.53,20878.74 r78 top
? "" "LED 5MM"#426 29088.68,21044.9 r78 top
? "" "LED 5MM"#427 28322.46,21207.99 r78 top
? "" "LED 5MM"#428 27550.12,21364.96 r78 top
? "" "LED 5MM"#429 29889.8,27122.11 r120 top
? "" "LED 5MM"#430 26878.4,24119.92 r150 top
? "" "LED 5MM"#431 33843.72,21460.71 r6 top
? "" "LED 5MM"#432 33656.65,21633.9 r12 top
? "" "LED 5MM"#433 33546.44,21400.51 r18 top
? "" "LED 5MM"#434 33319.55,21528.33 r24 top
? "" "LED 5MM"#435 33264.9,21279.19 r30 top
? "" "LED 5MM"#436 33012.99,21350.51 r36 top
? "" "LED 5MM"#437 33005.59,21089.35 r42 top
? "" "LED 5MM"#438 32756.46,21123.62 r48 top
? "" "LED 5MM"#439 32806.48,20863.38 r54 top
? "" "LED 5MM"#440 32550.87,20839.29 r60 top
? "" "LED 5MM"#441 32649.03,20598.5 r66 top
? "" "LED 5MM"#442 32405.47,20526.28 r72 top
? "" "LED 5MM"#443 32552.72,20303.09 r78 top
? "" "LED 5MM"#444 33996.75,27181.42 r0 top
? "" "LED 5MM"#445 34000.24,18322.13 r180 top
? "" "LED 5MM"#446 32518.46,19998.38 r270 top
? "" "LED 5MM"#447 40597.44,19992.54 r270 top
? "" "LED 5MM"#448 27781.46,16407.56 r300 top
? "" "LED 5MM"#449 28464.06,16801.48 r300 top
? "" "LED 5MM"#450 29481.02,17393.82 r300 top
? "" "LED 5MM"#451 29823.55,17587.85 r300 top
? "" "LED 5MM"#452 30502.79,17983.01 r300 top
? "" "LED 5MM"#453 31183.07,18383.38 r300 top
? "" "LED 5MM"#454 31867.4,18774.07 r300 top
? "" "LED 5MM"#455 40226.38,23589.45 r300 top
? "" "LED 5MM"#456 39538.88,23192.81 r300 top
? "" "LED 5MM"#457 38524.88,22609.67 r300 top
? "" "LED 5MM"#458 38177.07,22410.59 r300 top
? "" "LED 5MM"#459 37497.2,22020.31 r300 top
? "" "LED 5MM"#460 36813.62,21625.18 r300 top
? "" "LED 5MM"#461 36134.9,21227.34 r300 top
? "" "LED 5MM"#462 27977.85,17318.44 r294 top
? "" "LED 5MM"#463 28694.8,17638.46 r294 top
? "" "LED 5MM"#464 29414.86,17956.95 r294 top
? "" "LED 5MM"#465 30134.92,18275.43 r294 top
? "" "LED 5MM"#466 30855.2,18593.44 r294 top
? "" "LED 5MM"#467 31215.49,18756.51 r294 top
? "" "LED 5MM"#468 32294.33,19235.28 r294 top
? "" "LED 5MM"#469 40028.15,22675.85 r294 top
? "" "LED 5MM"#470 39314.19,22346.56 r294 top
? "" "LED 5MM"#471 38592.58,22045 r294 top
? "" "LED 5MM"#472 37866.36,21723.42 r294 top
? "" "LED 5MM"#473 37147.17,21405.18 r294 top
? "" "LED 5MM"#474 36786.04,21242.2 r294 top
? "" "LED 5MM"#475 35707.05,20765.22 r294 top
? "" "LED 5MM"#476 35473.66,19999.31 r270 top
? "" "LED 5MM"#477 35871.89,19997.46 r270 top
? "" "LED 5MM"#478 37050.93,19997.52 r270 top
? "" "LED 5MM"#479 39020.32,19998.66 r270 top
? "" "LED 5MM"#480 38229.47,20000.2 r270 top
? "" "LED 5MM"#481 37443.82,19997.19 r270 top
? "" "LED 5MM"#482 39809.61,19998.66 r270 top
? "" "LED 5MM"#483 32130.41,19997.46 r270 top
? "" "LED 5MM"#484 30948.78,19999.37 r270 top
? "" "LED 5MM"#485 30554.29,19997.19 r270 top
? "" "LED 5MM"#486 29768.74,20001.73 r270 top
? "" "LED 5MM"#487 28979.45,20000.2 r270 top
? "" "LED 5MM"#488 28196.3,19998.66 r270 top
? "" "LED 5MM"#489 27402.42,19998.68 r270 top
? "" "LED 5MM"#490 41145.18,20747.99 r276 top
? "" "LED 5MM"#491 26853.76,19250 r276 top
? "" "LED 5MM"#492 40363.56,20663.37 r276 top
? "" "LED 5MM"#493 39188.01,20541.79 r276 top
? "" "LED 5MM"#494 38797.04,20504.74 r276 top
? "" "LED 5MM"#495 38014.51,20426.95 r276 top
? "" "LED 5MM"#496 37232.32,20339.25 r276 top
? "" "LED 5MM"#497 36447.93,20256.77 r276 top
? "" "LED 5MM"#498 31554.37,19739.07 r276 top
? "" "LED 5MM"#499 27633.21,19327.85 r276 top
? "" "LED 5MM"#500 30772.87,19659.39 r276 top
? "" "LED 5MM"#501 29985.49,19579.69 r276 top
? "" "LED 5MM"#502 29203.85,19496.42 r276 top
? "" "LED 5MM"#503 28814.8,19455.53 r276 top
? "" "LED 5MM"#504 35827.44,20399.39 r282 top
? "" "LED 5MM"#505 36983.31,20640.24 r282 top
? "" "LED 5MM"#506 32170.24,19618.68 r282 top
? "" "LED 5MM"#507 37372.83,20722.48 r282 top
? "" "LED 5MM"#508 38141.77,20880.28 r282 top
? "" "LED 5MM"#509 38914.15,21043.37 r282 top
? "" "LED 5MM"#510 39686.54,21201.85 r282 top
? "" "LED 5MM"#511 40452.79,21364.96 r282 top
? "" "LED 5MM"#512 31013.6,19371.46 r282 top
? "" "LED 5MM"#513 30630.94,19287.52 r282 top
? "" "LED 5MM"#514 29859.53,19123.21 r282 top
? "" "LED 5MM"#515 29087.15,18955.49 r282 top
? "" "LED 5MM"#516 28319.39,18792.4 r282 top
? "" "LED 5MM"#517 27550.12,18617.03 r282 top
? "" "LED 5MM"#518 36339.59,20763.37 r288 top
? "" "LED 5MM"#519 37090.39,21007.76 r288 top
? "" "LED 5MM"#520 37841.26,21249.33 r288 top
? "" "LED 5MM"#521 38587.06,21489.58 r288 top
? "" "LED 5MM"#522 38963.39,21611.1 r288 top
? "" "LED 5MM"#523 40089.7,21974.25 r288 top
? "" "LED 5MM"#524 40834.37,22208.11 r288 top
? "" "LED 5MM"#525 31660.88,19237.13 r288 top
? "" "LED 5MM"#526 30914.8,18993.7 r288 top
? "" "LED 5MM"#527 30161.26,18749.01 r288 top
? "" "LED 5MM"#528 29413.34,18508.86 r288 top
? "" "LED 5MM"#529 29040.98,18386.22 r288 top
? "" "LED 5MM"#530 27913.23,18026.2 r288 top
? "" "LED 5MM"#531 27162.99,17789.88 r288 top
? "" "LED 5MM"#532 35517.2,21099.53 r306 top
? "" "LED 5MM"#533 32486.04,18902.81 r306 top
? "" "LED 5MM"#534 36470.26,21792.32 r306 top
? "" "LED 5MM"#535 36790.9,22029.69 r306 top
? "" "LED 5MM"#536 37429.41,22483.48 r306 top
? "" "LED 5MM"#537 38074.07,22946.61 r306 top
? "" "LED 5MM"#538 38707.97,23405.12 r306 top
? "" "LED 5MM"#539 39351.16,23866.73 r306 top
? "" "LED 5MM"#540 31535,18205.49 r306 top
? "" "LED 5MM"#541 31212.87,17977.46 r306 top
? "" "LED 5MM"#542 30576.5,17513.84 r306 top
? "" "LED 5MM"#543 29934.9,17049.17 r306 top
? "" "LED 5MM"#544 29307.17,16586.06 r306 top
? "" "LED 5MM"#545 28667.15,16124.51 r306 top
? "" "LED 5MM"#546 35833.92,21644.09 r312 top
? "" "LED 5MM"#547 36414.78,22171.63 r312 top
? "" "LED 5MM"#548 37005.61,22700.12 r312 top
? "" "LED 5MM"#549 37584.04,23225.84 r312 top
? "" "LED 5MM"#550 37884.82,23492.81 r312 top
? "" "LED 5MM"#551 38760.35,24279.07 r312 top
? "" "LED 5MM"#552 39345.79,24805.88 r312 top
? "" "LED 5MM"#553 32173.94,18353.62 r312 top
? "" "LED 5MM"#554 31584.74,17831.26 r312 top
? "" "LED 5MM"#555 30996.89,17298.25 r312 top
? "" "LED 5MM"#556 30416.72,16771.99 r312 top
? "" "LED 5MM"#557 30122.62,16507.58 r312 top
? "" "LED 5MM"#558 29251.81,15712.17 r312 top
? "" "LED 5MM"#559 28666.12,15191.12 r312 top
? "" "LED 5MM"#560 35254.17,21390.33 r318 top
? "" "LED 5MM"#561 32745.35,18612.93 r318 top
? "" "LED 5MM"#562 36044.23,22266.48 r318 top
? "" "LED 5MM"#563 36305.49,22559.11 r318 top
? "" "LED 5MM"#564 36835.51,23149.7 r318 top
? "" "LED 5MM"#565 37363.25,23728.21 r318 top
? "" "LED 5MM"#566 37892.52,24312.87 r318 top
? "" "LED 5MM"#567 38418.78,24900.67 r318 top
? "" "LED 5MM"#568 31958.23,17735.02 r318 top
? "" "LED 5MM"#569 31695.45,17445.2 r318 top
? "" "LED 5MM"#570 31167.32,16855.31 r318 top
? "" "LED 5MM"#571 30641.12,16269.11 r318 top
? "" "LED 5MM"#572 30110.31,15690.59 r318 top
? "" "LED 5MM"#573 29587.22,15096.71 r318 top
? "" "LED 5MM"#574 35445.89,21991.38 r324 top
? "" "LED 5MM"#575 35908.07,22634.33 r324 top
? "" "LED 5MM"#576 36377.2,23269.65 r324 top
? "" "LED 5MM"#577 36835.86,23900.76 r324 top
? "" "LED 5MM"#578 37070.9,24222.11 r324 top
? "" "LED 5MM"#579 37763.33,25174.53 r324 top
? "" "LED 5MM"#580 38233.8,25807.3 r324 top
? "" "LED 5MM"#581 32552.72,18010.96 r324 top
? "" "LED 5MM"#582 32092.87,17374.23 r324 top
? "" "LED 5MM"#583 31626.95,16737.83 r324 top
? "" "LED 5MM"#584 31165.26,16097.3 r324 top
? "" "LED 5MM"#585 30933.46,15784.45 r324 top
? "" "LED 5MM"#586 30248.82,14822.85 r324 top
? "" "LED 5MM"#587 29786.32,14191.75 r324 top
? "" "LED 5MM"#588 37301.75,25713.03 r330 top
? "" "LED 5MM"#589 36907.82,25029.86 r330 top
? "" "LED 5MM"#590 36515.47,24352.89 r330 top
? "" "LED 5MM"#591 36118.52,23671.28 r330 top
? "" "LED 5MM"#592 35723.56,22984.92 r330 top
? "" "LED 5MM"#593 35529.31,22642.48 r330 top
? "" "LED 5MM"#594 34939.31,21622.79 r330 top
? "" "LED 5MM"#595 33063.94,18382.32 r330 top
? "" "LED 5MM"#596 32474.07,17360.87 r330 top
? "" "LED 5MM"#597 32278.8,17017.97 r330 top
? "" "LED 5MM"#598 31888.92,16336.81 r330 top
? "" "LED 5MM"#599 31495.04,15656.75 r330 top
? "" "LED 5MM"#600 31091.93,14973.6 r330 top
? "" "LED 5MM"#601 30707.32,14293.56 r330 top
? "" "LED 5MM"#602 36921.1,26562.97 r336 top
? "" "LED 5MM"#603 36597.09,25842.28 r336 top
? "" "LED 5MM"#604 36120.06,24772.91 r336 top
? "" "LED 5MM"#605 35962.29,24405 r336 top
? "" "LED 5MM"#606 35647.68,23686.63 r336 top
? "" "LED 5MM"#607 35324.72,22963.62 r336 top
? "" "LED 5MM"#608 35005.06,22249.76 r336 top
? "" "LED 5MM"#609 32996.32,17756.28 r336 top
? "" "LED 5MM"#610 32674.8,17035.02 r336 top
? "" "LED 5MM"#611 32356.48,16313.37 r336 top
? "" "LED 5MM"#612 32038.83,15593.21 r336 top
? "" "LED 5MM"#613 31879.69,15239.78 r336 top
? "" "LED 5MM"#614 31399.7,14161.26 r336 top
? "" "LED 5MM"#615 31078.52,13444.29 r336 top
? "" "LED 5MM"#616 36043.19,26273.09 r342 top
? "" "LED 5MM"#617 35800.04,25525.29 r342 top
? "" "LED 5MM"#618 35552.32,24779.07 r342 top
? "" "LED 5MM"#619 35310.77,24028.25 r342 top
? "" "LED 5MM"#620 35070.67,23275.88 r342 top
? "" "LED 5MM"#621 34944.94,22900.87 r342 top
? "" "LED 5MM"#622 34584.61,21779.29 r342 top
? "" "LED 5MM"#623 33417.72,18223.98 r342 top
? "" "LED 5MM"#624 33055.67,17103.42 r342 top
? "" "LED 5MM"#625 32934.55,16727.01 r342 top
? "" "LED 5MM"#626 32692.07,15976.77 r342 top
? "" "LED 5MM"#627 32450.51,15229.01 r342 top
? "" "LED 5MM"#628 32205.87,14481.26 r342 top
? "" "LED 5MM"#629 31965.9,13727.36 r342 top
? "" "LED 5MM"#630 35495.79,27031.93 r348 top
? "" "LED 5MM"#631 35326.2,26254.63 r348 top
? "" "LED 5MM"#632 35086.12,25106.79 r348 top
? "" "LED 5MM"#633 35002.77,24716.51 r348 top
? "" "LED 5MM"#634 34841.87,23953.58 r348 top
? "" "LED 5MM"#635 34677.5,23179.37 r348 top
? "" "LED 5MM"#636 34513.29,22409.06 r348 top
? "" "LED 5MM"#637 33490.87,17593.29 r348 top
? "" "LED 5MM"#638 33327.7,16822.11 r348 top
? "" "LED 5MM"#639 33163.94,16053.05 r348 top
? "" "LED 5MM"#640 32997.75,15281.43 r348 top
? "" "LED 5MM"#641 32916.71,14899.76 r348 top
? "" "LED 5MM"#642 32670.57,13748.9 r348 top
? "" "LED 5MM"#643 32505.88,12983.52 r348 top
? "" "LED 5MM"#644 34191,21862.66 r354 top
? "" "LED 5MM"#645 34315.2,23035.16 r354 top
? "" "LED 5MM"#646 34358.15,23426.34 r354 top
? "" "LED 5MM"#647 34442.99,24211.34 r354 top
? "" "LED 5MM"#648 34524.55,24992.93 r354 top
? "" "LED 5MM"#649 34606.08,25780.71 r354 top
? "" "LED 5MM"#650 34689.21,26562.34 r354 top
? "" "LED 5MM"#651 33806.67,18139.69 r354 top
? "" "LED 5MM"#652 33680.81,16966.36 r354 top
? "" "LED 5MM"#653 33639.96,16573.72 r354 top
? "" "LED 5MM"#654 33556.77,15795.22 r354 top
? "" "LED 5MM"#655 33473.68,15005.92 r354 top
? "" "LED 5MM"#656 33390.59,14225.85 r354 top
? "" "LED 5MM"#657 33313.72,13435.04 r354 top
? "" "LED 5MM"#658 34002.09,21670.02 r0 top
? "" "LED 5MM"#659 34002.09,22460.92 r0 top
? "" "LED 5MM"#660 34003.31,23250.33 r0 top
? "" "LED 5MM"#661 33999.59,24038.15 r0 top
? "" "LED 5MM"#662 34000.21,24822.3 r0 top
? "" "LED 5MM"#663 34001.42,25220.65 r0 top
? "" "LED 5MM"#664 33999.92,26396.18 r0 top
? "" "LED 5MM"#665 34001.16,17541.42 r0 top
? "" "LED 5MM"#666 34003.31,16755.39 r0 top
? "" "LED 5MM"#667 34001.26,15965.18 r0 top
? "" "LED 5MM"#668 34000.15,15176.38 r0 top
? "" "LED 5MM"#669 33999.88,14782.82 r0 top
? "" "LED 5MM"#670 33999.92,13607.36 r0 top
? "" "LED 5MM"#671 33995.32,12816.51 r0 top
? "" "LED 5MM"#672 41125.49,24105.57 r30 top
? "" "LED 5MM"#673 26871.24,15896.65 r30 top
? "" "LED 5MM"#674 38106.93,27121.08 r60 top
? "" "LED 5MM"#675 29871.38,12883.21 r60 top
? "" "LED 5MM"#676 34000,11840 r90 top
? "" "LED 5MM"#677 35655.18,20177.13 r276 top
? "" "LED 5MM"#678 32329.53,19825.22 r276 top
? "" "LED 5MM"#679 35443.11,20302.17 r282 top
? "" "LED 5MM"#680 32551.79,19700.18 r282 top
? "" "LED 5MM"#681 35582.95,20515.16 r288 top
? "" "LED 5MM"#682 32402.7,19477.91 r288 top
? "" "LED 5MM"#683 35349.57,20594.8 r294 top
? "" "LED 5MM"#684 32651.81,19390.87 r294 top
? "" "LED 5MM"#685 35442.18,20833.74 r300 top
? "" "LED 5MM"#686 32539.76,19165.83 r300 top
? "" "LED 5MM"#687 35187.5,20865.24 r306 top
? "" "LED 5MM"#688 32805.55,19128.78 r306 top
? "" "LED 5MM"#689 35242.14,21110.65 r312 top
? "" "LED 5MM"#690 32744.43,18879.65 r312 top
? "" "LED 5MM"#691 34988.39,21094.9 r318 top
? "" "LED 5MM"#692 33008.37,18905.59 r318 top
? "" "LED 5MM"#693 34980.98,21347.74 r324 top
? "" "LED 5MM"#694 33010.22,18641.63 r324 top
? "" "LED 5MM"#695 34741.12,21273.64 r330 top
? "" "LED 5MM"#696 33261.2,18721.28 r330 top
? "" "LED 5MM"#697 34680.93,21524.63 r336 top
? "" "LED 5MM"#698 33313.05,18465.69 r336 top
? "" "LED 5MM"#699 34338.17,21036.18 r342 top
? "" "LED 5MM"#700 33538.11,18596.26 r342 top
? "" "LED 5MM"#701 34350.29,21632.05 r348 top
? "" "LED 5MM"#702 33654.78,18357.32 r348 top
? "" "LED 5MM"#703 33845.57,18528.66 r354 top
? "" "LED 5MM"#704 34148.4,21465.35 r354 top
? "" "LED 5MM"#705 32785.22,18331.63 r324 top
? "" "LED 5MM"#706 33158.05,18115.69 r336 top
? "" "LED 5MM"#707 33574.78,17977.32 r348 top
? "" "LED 5MM"#708 34005.24,17937.13 r180 top
? "" "LED 5MM"#709 34429,17979.17 r192 top
? "" "LED 5MM"#710 34844.25,18116.24 r204 top
? "" "LED 5MM"#711 35214.68,18326.28 r216 top
? "" "LED 5MM"#712 35534,18617.44 r228 top
? "" "LED 5MM"#713 35792.74,18971.75 r240 top
? "" "LED 5MM"#714 35971.65,19362.19 r252 top
? "" "LED 5MM"#715 36057.05,19780.22 r264 top
? "" "LED 5MM"#716 36060.18,20217.13 r276 top
? "" "LED 5MM"#717 35967.95,20640.16 r288 top
? "" "LED 5MM"#718 35792.18,21033.74 r300 top
? "" "LED 5MM"#719 35537.14,21385.65 r312 top
? "" "LED 5MM"#720 35215.98,21672.74 r324 top
? "" "LED 5MM"#721 34840.93,21889.63 r336 top
? "" "LED 5MM"#722 34430.29,22022.05 r348 top
? "" "LED 5MM"#723 34002.09,22065.02 r0 top
? "" "LED 5MM"#724 33571.65,22018.9 r12 top
? "" "LED 5MM"#725 33159.55,21883.33 r24 top
? "" "LED 5MM"#726 32782.99,21665.51 r36 top
? "" "LED 5MM"#727 32466.46,21383.62 r48 top
? "" "LED 5MM"#728 32210.87,21034.29 r60 top
? "" "LED 5MM"#729 32035.47,20636.28 r72 top
? "" "LED 5MM"#730 31948.9,20226.22 r264 top
? "" "LED 5MM"#731 31944.53,19790.22 r276 top
? "" "LED 5MM"#732 32037.7,19362.91 r288 top
? "" "LED 5MM"#733 32209.76,18975.83 r300 top
? "" "LED 5MM"#734 32464.43,18624.65 r312 top
? "" "LED 5MM"#735 31934.33,19080.28 r294 top
? "" "LED 5MM"#736 32490.35,18322.93 r318 top
? "" "LED 5MM"#737 32868.94,18042.32 r330 top
? "" "LED 5MM"#738 33297.72,17853.98 r342 top
? "" "LED 5MM"#739 33766.67,17749.69 r354 top
? "" "LED 5MM"#740 34240.63,17747.83 r186 top
? "" "LED 5MM"#741 34701.83,17847.11 r198 top
? "" "LED 5MM"#742 35133.39,18039.55 r210 top
? "" "LED 5MM"#743 35514.17,18321.08 r222 top
? "" "LED 5MM"#744 35831.63,18672.81 r234 top
? "" "LED 5MM"#745 36067.97,19076.2 r246 top
? "" "LED 5MM"#746 36217.44,19529.06 r258 top
? "" "LED 5MM"#747 36261.89,19997.46 r270 top
? "" "LED 5MM"#748 36212.44,20484.39 r282 top
? "" "LED 5MM"#749 36067.05,20925.22 r294 top
? "" "LED 5MM"#750 35832.2,21329.53 r306 top
? "" "LED 5MM"#751 35519.17,21680.33 r318 top
? "" "LED 5MM"#752 35134.31,21962.79 r330 top
? "" "LED 5MM"#753 34704.61,22154.29 r342 top
? "" "LED 5MM"#754 34231,22252.66 r354 top
? "" "LED 5MM"#755 33762.97,22249.86 r6 top
? "" "LED 5MM"#756 33300.12,22149.29 r18 top
? "" "LED 5MM"#757 32873.56,21960 r30 top
? "" "LED 5MM"#758 32484.19,21674.65 r42 top
? "" "LED 5MM"#759 32171.04,21325.83 r54 top
? "" "LED 5MM"#760 31933.4,20915.57 r66 top
? "" "LED 5MM"#761 31790.24,20470.14 r78 top
? "" "LED 5MM"#762 31740.41,19997.46 r270 top
? "" "LED 5MM"#763 31790.24,19538.68 r282 top
? "" "LED 5MM"#764 34279.92,17355.28 r186 top
? "" "LED 5MM"#765 34826.83,17467.11 r198 top
? "" "LED 5MM"#766 35333.82,17694.23 r210 top
? "" "LED 5MM"#767 35783.92,18021.14 r222 top
? "" "LED 5MM"#768 36156.63,18437.81 r234 top
? "" "LED 5MM"#769 36432.97,18916.2 r246 top
? "" "LED 5MM"#770 36607.44,19444.06 r258 top
? "" "LED 5MM"#771 36661.89,19997.46 r270 top
? "" "LED 5MM"#772 36602.44,20559.39 r282 top
? "" "LED 5MM"#773 36427.05,21085.22 r294 top
? "" "LED 5MM"#774 36152.2,21559.53 r306 top
? "" "LED 5MM"#775 35779.17,21975.33 r318 top
? "" "LED 5MM"#776 35329.31,22297.79 r330 top
? "" "LED 5MM"#777 34824.61,22519.29 r342 top
? "" "LED 5MM"#778 34271,22637.66 r354 top
? "" "LED 5MM"#779 33717.97,22639.86 r6 top
? "" "LED 5MM"#780 33180.12,22519.29 r18 top
? "" "LED 5MM"#781 32678.56,22295 r30 top
? "" "LED 5MM"#782 32224.19,21959.65 r42 top
? "" "LED 5MM"#783 31851.04,21550.83 r54 top
? "" "LED 5MM"#784 31578.4,21075.57 r66 top
? "" "LED 5MM"#785 31405.24,20550.14 r78 top
? "" "LED 5MM"#786 31350.41,20002.46 r270 top
? "" "LED 5MM"#787 31400.24,19458.68 r282 top
? "" "LED 5MM"#788 31579.33,18915.28 r294 top
? "" "LED 5MM"#789 31851.04,18437.81 r306 top
? "" "LED 5MM"#790 32176.04,18667.81 r306 top
? "" "LED 5MM"#791 32225.35,18027.93 r318 top
? "" "LED 5MM"#792 32673.94,17702.32 r330 top
? "" "LED 5MM"#793 33177.72,17473.98 r342 top
? "" "LED 5MM"#794 33721.67,17354.69 r354 top
? "" "LED 5MM"#795 35675.89,22311.38 r324 top
? "" "LED 5MM"#796 35165.06,22604.76 r336 top
? "" "LED 5MM"#797 34593.29,22794.06 r348 top
? "" "LED 5MM"#798 34002.09,22855.92 r0 top
? "" "LED 5MM"#799 33406.79,22789.06 r12 top
? "" "LED 5MM"#800 32840.04,22605.14 r24 top
? "" "LED 5MM"#801 32318.09,22302.68 r36 top
? "" "LED 5MM"#802 31883.01,21910.57 r48 top
? "" "LED 5MM"#803 31530.18,21426.97 r60 top
? "" "LED 5MM"#804 31285.88,20880.57 r72 top
? "" "LED 5MM"#805 31163.44,20306.04 r264 top
? "" "LED 5MM"#806 31164.37,19704.07 r276 top
? "" "LED 5MM"#807 31285.88,19117.13 r288 top
? "" "LED 5MM"#808 31527.4,18574.07 r300 top
? "" "LED 5MM"#809 31883.94,18093.62 r312 top
? "" "LED 5MM"#810 32322.72,17690.96 r324 top
? "" "LED 5MM"#811 32836.32,17401.28 r336 top
? "" "LED 5MM"#812 33410.87,17213.29 r348 top
? "" "LED 5MM"#813 34001.16,17146.42 r0 top
? "" "LED 5MM"#814 36153.62,17039.27 r216 top
? "" "LED 5MM"#815 36718.37,17552.01 r228 top
? "" "LED 5MM"#816 37165.79,18174.13 r240 top
? "" "LED 5MM"#817 37473.98,18875.81 r252 top
? "" "LED 5MM"#818 37624.07,19616.81 r264 top
? "" "LED 5MM"#819 37622.32,20379.25 r276 top
? "" "LED 5MM"#820 37460.39,21127.76 r288 top
? "" "LED 5MM"#821 37148.62,21815.18 r300 top
? "" "LED 5MM"#822 36699.78,22426.63 r312 top
? "" "LED 5MM"#823 36133.07,22939.33 r324 top
? "" "LED 5MM"#824 35474.72,23308.62 r336 top
? "" "LED 5MM"#825 34757.5,23544.37 r348 top
? "" "LED 5MM"#826 33998.31,23620.33 r0 top
? "" "LED 5MM"#827 33248.44,23539.37 r12 top
? "" "LED 5MM"#828 32526.22,23302.15 r24 top
? "" "LED 5MM"#829 31867.19,22929.41 r36 top
? "" "LED 5MM"#830 31306.16,22428.05 r48 top
? "" "LED 5MM"#831 30856.57,21809.43 r60 top
? "" "LED 5MM"#832 30546.22,21124.92 r72 top
? "" "LED 5MM"#833 30386.46,20387.78 r264 top
? "" "LED 5MM"#834 30382.87,19619.39 r276 top
? "" "LED 5MM"#835 30534.8,18873.7 r288 top
? "" "LED 5MM"#836 30838.07,18178.38 r300 top
? "" "LED 5MM"#837 31289.74,17556.26 r312 top
? "" "LED 5MM"#838 31852.87,17044.23 r324 top
? "" "LED 5MM"#839 32509.8,16665.02 r336 top
? "" "LED 5MM"#840 33242.7,16422.11 r348 top
? "" "LED 5MM"#841 33998.31,16340.39 r0 top
? "" "LED 5MM"#842 34766.75,16424.94 r192 top
? "" "LED 5MM"#843 35492.56,16655.02 r204 top
? "" "LED 5MM"#844 35929.68,16656.22 r210 top
? "" "LED 5MM"#845 36582.41,17138.19 r222 top
? "" "LED 5MM"#846 37117.36,17737.58 r234 top
? "" "LED 5MM"#847 37514.91,18430.15 r246 top
? "" "LED 5MM"#848 37762.24,19199.21 r258 top
? "" "LED 5MM"#849 37844.32,19998.98 r270 top
? "" "LED 5MM"#850 35802.06,15958.58 r204 top
? "" "LED 5MM"#851 36605.13,16417.79 r216 top
? "" "LED 5MM"#852 37289.54,17037.36 r228 top
? "" "LED 5MM"#853 37836.33,17787.99 r240 top
? "" "LED 5MM"#854 38210.94,18633.98 r252 top
? "" "LED 5MM"#855 38406.17,19534.94 r264 top
? "" "LED 5MM"#856 38407.04,20464.74 r276 top
? "" "LED 5MM"#857 38212.06,21369.59 r288 top
? "" "LED 5MM"#858 37842.07,22215.59 r300 top
? "" "LED 5MM"#859 37294.05,22965.84 r312 top
? "" "LED 5MM"#860 36605.86,23585.76 r324 top
? "" "LED 5MM"#861 35807.29,24050 r336 top
? "" "LED 5MM"#862 34922.77,24336.51 r348 top
? "" "LED 5MM"#863 34000.21,24432.3 r0 top
? "" "LED 5MM"#864 33077.32,24334.29 r12 top
? "" "LED 5MM"#865 32198.71,24045 r24 top
? "" "LED 5MM"#866 31395.27,23581.51 r36 top
? "" "LED 5MM"#867 30710.35,22966.61 r48 top
? "" "LED 5MM"#868 30164.07,22215.77 r60 top
? "" "LED 5MM"#869 29783.83,21369.09 r72 top
? "" "LED 5MM"#870 29594.34,20468.13 r264 top
? "" "LED 5MM"#871 29593.85,19536.42 r276 top
? "" "LED 5MM"#872 29788.33,18628.85 r288 top
? "" "LED 5MM"#873 30163.55,17787.85 r300 top
? "" "LED 5MM"#874 30711.72,17036.98 r312 top
? "" "LED 5MM"#875 31400.26,16417.3 r324 top
? "" "LED 5MM"#876 32198.83,15958.21 r336 top
? "" "LED 5MM"#877 33082.75,15666.44 r348 top
? "" "LED 5MM"#878 34000.15,15576.38 r0 top
? "" "LED 5MM"#879 34922.07,15666.71 r192 top
? "" "LED 5MM"#880 35424.25,15600.94 r198 top
? "" "LED 5MM"#881 36315.87,15994.06 r210 top
? "" "LED 5MM"#882 37098.25,16562.56 r222 top
? "" "LED 5MM"#883 37744.84,17281.1 r234 top
? "" "LED 5MM"#884 38227.97,18116.95 r246 top
? "" "LED 5MM"#885 38527.62,19041.65 r258 top
? "" "LED 5MM"#886 38625.32,19998.66 r270 top
? "" "LED 5MM"#887 38524.15,20963.37 r282 top
? "" "LED 5MM"#888 38227.58,21885 r294 top
? "" "LED 5MM"#889 37749.07,22711.61 r306 top
? "" "LED 5MM"#890 37098.25,23438.21 r318 top
? "" "LED 5MM"#891 36320.47,24012.89 r330 top
? "" "LED 5MM"#892 35432.32,24399.07 r342 top
? "" "LED 5MM"#893 34484.55,24602.93 r354 top
? "" "LED 5MM"#894 33510.22,24599.49 r6 top
? "" "LED 5MM"#895 32572.44,24402.54 r18 top
? "" "LED 5MM"#896 31688.9,24006.34 r30 top
? "" "LED 5MM"#897 30899.96,23437.83 r42 top
? "" "LED 5MM"#898 30256.46,22719.69 r54 top
? "" "LED 5MM"#899 29775.26,21876.91 r66 top
? "" "LED 5MM"#900 29473.68,20964.9 r78 top
? "" "LED 5MM"#901 29374.45,20000.2 r270 top
? "" "LED 5MM"#902 29477.15,19045.49 r282 top
? "" "LED 5MM"#903 29774.86,18116.95 r294 top
? "" "LED 5MM"#904 30259.9,17279.17 r306 top
? "" "LED 5MM"#905 30901.12,16564.11 r318 top
? "" "LED 5MM"#906 31690.04,15996.75 r330 top
? "" "LED 5MM"#907 32570.51,15604.01 r342 top
? "" "LED 5MM"#908 33513.68,15400.92 r354 top
? "" "LED 5MM"#909 34484.53,15402.87 r186 top
? "" "LED 5MM"#910 35173.05,14514.76 r192 top
? "" "LED 5MM"#911 35664.25,14855.94 r198 top
? "" "LED 5MM"#912 36279.68,14878.62 r204 top
? "" "LED 5MM"#913 36705.87,15319.06 r210 top
? "" "LED 5MM"#914 37301.3,15458.29 r216 top
? "" "LED 5MM"#915 37623.25,15977.56 r222 top
? "" "LED 5MM"#916 38167.14,16239.51 r228 top
? "" "LED 5MM"#917 38379.84,16816.1 r234 top
? "" "LED 5MM"#918 38857.18,17198.82 r240 top
? "" "LED 5MM"#919 38949.96,17805.37 r246 top
? "" "LED 5MM"#920 39330.32,18256.22 r252 top
? "" "LED 5MM"#921 39292.62,18881.65 r258 top
? "" "LED 5MM"#922 39581.48,19417.46 r264 top
? "" "LED 5MM"#923 39414.61,19998.66 r270 top
? "" "LED 5MM"#924 39578.01,20586.79 r276 top
? "" "LED 5MM"#925 39301.54,21111.85 r282 top
? "" "LED 5MM"#926 39338.39,21726.1 r288 top
? "" "LED 5MM"#927 38957.58,22185 r294 top
? "" "LED 5MM"#928 38859.88,22799.67 r300 top
? "" "LED 5MM"#929 38404.75,23153.27 r306 top
? "" "LED 5MM"#930 38179.82,23747.81 r312 top
? "" "LED 5MM"#931 37627.52,24022.87 r318 top
? "" "LED 5MM"#932 37304.36,24536.18 r324 top
? "" "LED 5MM"#933 36707.82,24689.86 r330 top
? "" "LED 5MM"#934 36285.06,25122.91 r336 top
? "" "LED 5MM"#935 35680.04,25150.29 r342 top
? "" "LED 5MM"#936 35171.12,25486.79 r348 top
? "" "LED 5MM"#937 34566.08,25380.71 r354 top
? "" "LED 5MM"#938 34001.42,25610.65 r0 top
? "" "LED 5MM"#939 33433.68,25384.55 r6 top
? "" "LED 5MM"#940 32826.71,25485.26 r12 top
? "" "LED 5MM"#941 32322.79,25147.22 r18 top
? "" "LED 5MM"#942 31719.69,25126.77 r24 top
? "" "LED 5MM"#943 31293.9,24686.34 r30 top
? "" "LED 5MM"#944 30700.37,24534.03 r36 top
? "" "LED 5MM"#945 30380.31,24017.87 r42 top
? "" "LED 5MM"#946 29830.69,23746.28 r48 top
? "" "LED 5MM"#947 29619.09,23179.35 r54 top
? "" "LED 5MM"#948 29149.09,22805.04 r60 top
? "" "LED 5MM"#949 29055.26,22196.91 r66 top
? "" "LED 5MM"#950 28662.91,21734.19 r72 top
? "" "LED 5MM"#951 28712.46,21127.99 r78 top
? "" "LED 5MM"#952 28424.8,20589.86 r264 top
? "" "LED 5MM"#953 28589.45,20005.2 r270 top
? "" "LED 5MM"#954 28419.8,19415.53 r276 top
? "" "LED 5MM"#955 28709.39,18882.4 r282 top
? "" "LED 5MM"#956 28665.98,18281.22 r288 top
? "" "LED 5MM"#957 29054.8,17803.46 r294 top
? "" "LED 5MM"#958 29146.02,17193.82 r300 top
? "" "LED 5MM"#959 29622.17,16826.06 r306 top
? "" "LED 5MM"#960 29832.62,16252.58 r312 top
? "" "LED 5MM"#961 30380.31,15980.59 r318 top
? "" "LED 5MM"#962 30713.46,15469.45 r324 top
? "" "LED 5MM"#963 31296.93,15313.6 r330 top
? "" "LED 5MM"#964 31719.69,14879.78 r336 top
? "" "LED 5MM"#965 32325.87,14851.26 r342 top
? "" "LED 5MM"#966 32836.71,14514.76 r348 top
? "" "LED 5MM"#967 33435.59,14615.85 r354 top
? "" "LED 5MM"#968 33999.88,14397.82 r0 top
? "" "LED 5MM"#969 34569.15,14623.94 r186 top
? "" "LED 5MM"#970 34000,11600 r90 top
? "" "LED 5MM"#971 34200,11720 r90 top
? "" "LED 5MM"#972 33780,11740 r90 top
? "" "LED 5MM"#973 34000,28400 r90 top
? "" "LED 5MM"#974 34000,28140 r90 top
? "" "LED 5MM"#975 34220,28280 r90 top
? "" "LED 5MM"#976 33780,28260 r90 top
? "" "LED 5MM"#977 42260,20140 r90 top
? "" "LED 5MM"#978 42260,19860 r90 top
? "" "LED 5MM"#979 42443.31,20002.66 r90 top
? "" "LED 5MM"#980 42080,20000 r90 top
? "" "LED 5MM"#981 25740,20140 r90 top
? "" "LED 5MM"#982 25740,19860 r90 top
? "" "LED 5MM"#983 25520,20000 r90 top
? "" "LED 5MM"#984 25940,20000 r90 top

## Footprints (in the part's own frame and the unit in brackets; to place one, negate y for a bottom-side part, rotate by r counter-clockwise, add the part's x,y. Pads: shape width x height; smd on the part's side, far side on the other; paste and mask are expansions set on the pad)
"LED 5MM"#1 [mm]
  round 1.8 hole 0.9: 1967(-1.016,0) 1968(1.016,0)
  silkscreen extent -2.5,-2.5 2.5,2.5
"LED 5MM"#2 [mm]
  round 1.8 hole 0.9: 1965(1.016,0) 1966(-1.016,0)
  silkscreen extent -2.5,-2.5 2.5,2.5
"LED 5MM"#3 [mm]
  round 1.8 hole 0.9: 1963(-1.016,0) 1964(1.016,0)
  silkscreen extent -2.5,-2.5 2.5,2.5
"LED 5MM"#4 [mm]
  round 1.8 hole 0.9: 1961(1.016,0) 1962(-1.016,0)
  silkscreen extent -2.5,-2.5 2.5,2.5
"LED 5MM"#5 [mm]
  round 1.8 hole 0.9: 1959(-1.016,0) 1960(1.016,0)
  silkscreen extent -2.5,-2.5 2.5,2.5
"LED 5MM"#6 [mm]
  round 1.8 hole 0.9: 1957(1.016,0) 1958(-1.016,0)
  silkscreen extent -2.5,-2.5 2.5,2.5
"LED 5MM"#7 [mm]
  round 1.8 hole 0.9: 1955(1.016,0) 1956(-1.016,0)
  silkscreen extent -2.5,-2.5 2.5,2.5
"LED 5MM"#8 [mm]
  round 1.8 hole 0.9: 1953(-1.016,0) 1954(1.016,0)
  silkscreen extent -2.5,-2.5 2.5,2.5
"LED 5MM"#9 [mm]
  round 1.8 hole 0.9: 1951(1.016,0) 1952(-1.016,0)
  silkscreen extent -2.5,-2.5 2.5,2.5
"LED 5MM"#10 [mm]
  round 1.8 hole 0.9: 1949(1.016,0) 1950(-1.016,0)
  silkscreen extent -2.5,-2.5 2.5,2.5
"LED 5MM"#11 [mm]
  round 1.8 hole 0.9: 1947(1.016,0) 1948(-1.016,0)
  silkscreen extent -2.5,-2.5 2.5,2.5
"LED 5MM"#12 [mm]
  round 1.8 hole 0.9: 1945(-1.016,0) 1946(1.016,0)
  silkscreen extent -2.5,-2.5 2.5,2.5
"LED 5MM"#13 [mm]
  round 1.8 hole 0.9: 1943(1.016,0) 1944(-1.016,0)
  silkscreen extent -2.5,-2.5 2.5,2.5
"LED 5MM"#14 [mm]
  round 1.8 hole 0.9: 1941(1.016,0) 1942(-1.016,0)
  silkscreen extent -2.5,-2.5 2.5,2.5
"LED 5MM"#15 [mm]
  round 1.8 hole 0.9: 1939(-1.016,0) 1940(1.016,0)
  silkscreen extent -2.5,-2.5 2.5,2.5
"LED 5MM"#16 [mm]
  round 1.8 hole 0.9: 1937(1.016,0) 1938(-1.016,0)
  silkscreen extent -2.5,-2.5 2.5,2.5
"LED 5MM"#17 [mm]
  round 1.8 hole 0.9: 1935(-1.016,0) 1936(1.016,0)
  silkscreen extent -2.5,-2.5 2.5,2.5
"LED 5MM"#18 [mm]
  round 1.8 hole 0.9: 1933(1.016,0) 1934(-1.016,0)
  silkscreen extent -2.5,-2.5 2.5,2.5
"LED 5MM"#19 [mm]
  round 1.8 hole 0.9: 1931(1.016,0) 1932(-1.016,0)
  silkscreen extent -2.5,-2.5 2.5,2.5
"LED 5MM"#20 [mm]
  round 1.8 hole 0.9: 1929(1.016,0) 1930(-1.016,0)
  silkscreen extent -2.5,-2.5 2.5,2.5
"LED 5MM"#21 [mm]
  round 1.8 hole 0.9: 1927(-1.016,0) 1928(1.016,0)
  silkscreen extent -2.5,-2.5 2.5,2.5
"LED 5MM"#22 [mm]
  round 1.8 hole 0.9: 1925(1.016,0) 1926(-1.016,0)
  silkscreen extent -2.5,-2.5 2.5,2.5
"LED 5MM"#23 [mm]
  round 1.8 hole 0.9: 1923(-1.016,0) 1924(1.016,0)
  silkscreen extent -2.5,-2.5 2.5,2.5
"LED 5MM"#24 [mm]
  round 1.8 hole 0.9: 1921(-1.016,0) 1922(1.016,0)
  silkscreen extent -2.5,-2.5 2.5,2.5
"LED 5MM"#25 [mm]
  round 1.8 hole 0.9: 1919(-1.016,0) 1920(1.016,0)
  silkscreen extent -2.5,-2.5 2.5,2.5
"LED 5MM"#26 [mm]
  round 1.8 hole 0.9: 1917(-1.016,0) 1918(1.016,0)
  silkscreen extent -2.5,-2.5 2.5,2.5
"LED 5MM"#27 [mm]
  round 1.8 hole 0.9: 1915(-1.016,0) 1916(1.016,0)
  silkscreen extent -2.5,-2.5 2.5,2.5
"LED 5MM"#28 [mm]
  round 1.8 hole 0.9: 1913(1.016,0) 1914(-1.016,0)
  silkscreen extent -2.5,-2.5 2.5,2.5
"LED 5MM"#29 [mm]
  round 1.8 hole 0.9: 1911(1.016,0) 1912(-1.016,0)
  silkscreen extent -2.5,-2.5 2.5,2.5
"LED 5MM"#30 [mm]
  round 1.8 hole 0.9: 1909(-1.016,0) 1910(1.016,0)
  silkscreen extent -2.5,-2.5 2.5,2.5
"LED 5MM"#31 [mm]
  round 1.8 hole 0.9: 1907(1.016,0) 1908(-1.016,0)
  silkscreen extent -2.5,-2.5 2.5,2.5
"LED 5MM"#32 [mm]
  round 1.8 hole 0.9: 1905(1.016,0) 1906(-1.016,0)
  silkscreen extent -2.5,-2.5 2.5,2.5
